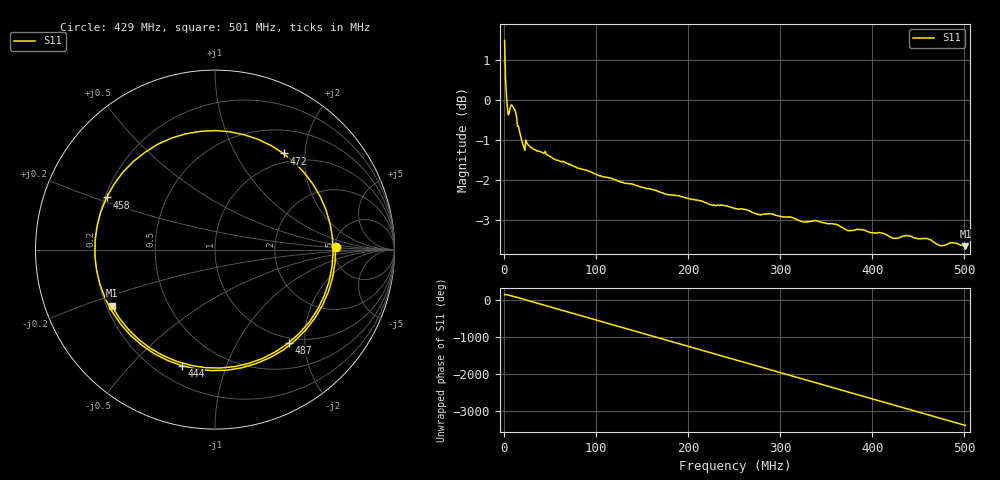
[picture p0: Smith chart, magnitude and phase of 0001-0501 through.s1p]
! NanoVNA-App by SYSJOINT et al v1.1.209 (+OD18)
! Date: 2025-09-17 10:01:50
! Start: 1MHz Stop: 501MHz Points: 501
! S-Parameter data: F S11
# Hz S RI R 50
!  Frequency  S11_Real  S11_Imag
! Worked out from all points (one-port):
!   501 points, 1 MHz to 501 MHz, reference 50 ohm
!   lowest |S11| = -3.7 dB at 501 MHz (marker M1), VSWR 4.81, Z = 11 - j12.1 ohm
!   |S11| at or under -10 dB: nowhere
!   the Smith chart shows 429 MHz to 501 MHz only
!   S11 on the Smith chart (normalised r, x): 429 MHz: 5.08, +0.26; 444 MHz: 0.30, -0.71; 458 MHz: 0.21, +0.22; 472 MHz: 0.85, +1.60; 487 MHz: 0.91, -1.68; 501 MHz: 0.22, -0.24
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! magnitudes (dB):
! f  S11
! 1 MHz  1.5
! 4 MHz  -0.2
! 5 MHz  -0.4
! 6 MHz  -0.3
! 9 MHz  -0.1
! 11 MHz  -0.2
! 21 MHz  -1.1
! 26 MHz  -1.1
! 34 MHz  -1.2
! 64 MHz  -1.5
! 126 MHz  -2.1
! 189 MHz  -2.4
! 251 MHz  -2.7
! 277 MHz  -2.9
! 290 MHz  -2.9
! 314 MHz  -3.0
! 326 MHz  -3.1
! 339 MHz  -3.0
! 359 MHz  -3.1
! 376 MHz  -3.3
! 389 MHz  -3.3
! 429 MHz  -3.5
! 439 MHz  -3.4
! 444 MHz  -3.4
! 458 MHz  -3.5
! 472 MHz  -3.6
! 487 MHz  -3.6
! 501 MHz  -3.7
